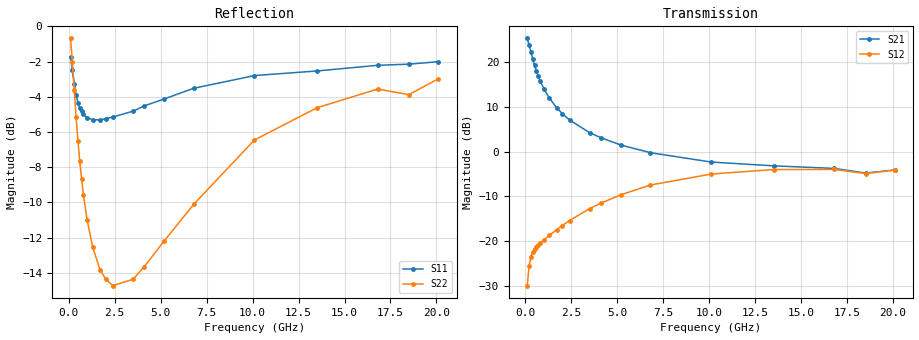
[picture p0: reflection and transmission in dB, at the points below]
!  Infineon Technologies AG
! BFR380L3 , PF131585-7, No.6, Th 09.10.01, soldered on pcb-board, measured with PP GSG850
!  Vce=1.5 V,  Ic=6.0 mA
! Common Emitter S-Parameters:  15. November 2001
#  GHz  S  MA  R  50
! f  S11  S21  S12  S22
! GHz  Mag  Ang  Mag  Ang  Mag  Ang  Mag  Ang
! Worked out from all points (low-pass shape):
!   201 points, 100 MHz to 20.1 GHz, reference 50 ohm
!   highest |S21| = 25.27 dB at 100 MHz (marker M1); lowest = -4.8 dB at 18.5 GHz (marker M2)
!   |S21| within 3 dB of the highest: start of sweep to 296.5 MHz
!   lowest |S11| = -5.3 dB at 1.7 GHz (marker M3), VSWR 3.37, Z = 14.8 + j0.141 ohm
!   |S11| at or under -10 dB: nowhere
!   |S22| runs from -14.8 to -0.7 dB; largest |S21 - S12| = 18
!   S11 on the Smith chart (normalised r, x): 100 MHz: 1.02, -2.88; 300 MHz: 0.37, -0.97; 1 GHz: 0.30, -0.20; 4.1 GHz: 0.29, +0.38; 10.1 GHz: 0.39, +1.17; 20.1 GHz: 0.96, +2.56
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0.1  0.819 -34.7  18.34 157.6  0.03183 72.0  0.9253 -22.2
0.2  0.7524 -64.1  15.53 139.7  0.05274 59.3  0.7909 -39.8
0.3  0.6885 -87.4  12.9 126.8  0.06679 51.2  0.6582 -52.4
0.4  0.6398 -104.5  10.77 117.3  0.07529 46.5  0.5528 -61.6
0.5  0.6078 -117.8  9.139 110.2  0.08166 43.9  0.4736 -68.4
0.6  0.5867 -128.6  7.891 104.6  0.08663 42.9  0.4142 -73.7
0.7  0.5741 -137.2  6.933 100.0  0.09085 42.3  0.3682 -78.1
0.8  0.5626 -144.2  6.162 96.1  0.09515 42.6  0.3324 -81.8
1  0.5509 -155.5  5.043 89.6  0.1033 43.4  0.282 -88.0
1.3  0.5438 -167.9  3.957 81.9  0.1159 45.4  0.2362 -95.9
1.7  0.5427 179.6  3.086 73.3  0.1343 47.8  0.2038 -104.9
2  0.5469 172.2  2.657 67.7  0.1489 49.0  0.1918 -110.9
2.4  0.5531 163.6  2.254 60.9  0.1698 50.0  0.1835 -118.9
3.5  0.5747 144.4  1.62 44.7  0.2312 49.4  0.1914 -138.6
4.1  0.5947 135.8  1.428 37.3  0.265 47.9  0.2076 -150.1
5.2  0.6227 121.9  1.181 24.9  0.3297 42.4  0.2462 -167.1
6.8  0.6676 103.9  0.9711 10.7  0.4228 33.5  0.3126 167.8
10.1  0.7254 77.2  0.7639 -8.3  0.561 11.7  0.4759 129.9
13.5  0.7476 59.6  0.6928 -22.6  0.6297 -9.8  0.5876 99.4
16.8  0.7758 47.6  0.6484 -33.5  0.6316 -26.0  0.6641 77.1
18.5  0.7816 45.4  0.5752 -40.7  0.5674 -34.6  0.6404 71.3
20.1  0.7944 38.3  0.6219 -44.7  0.6209 -39.6  0.7104 60.6
